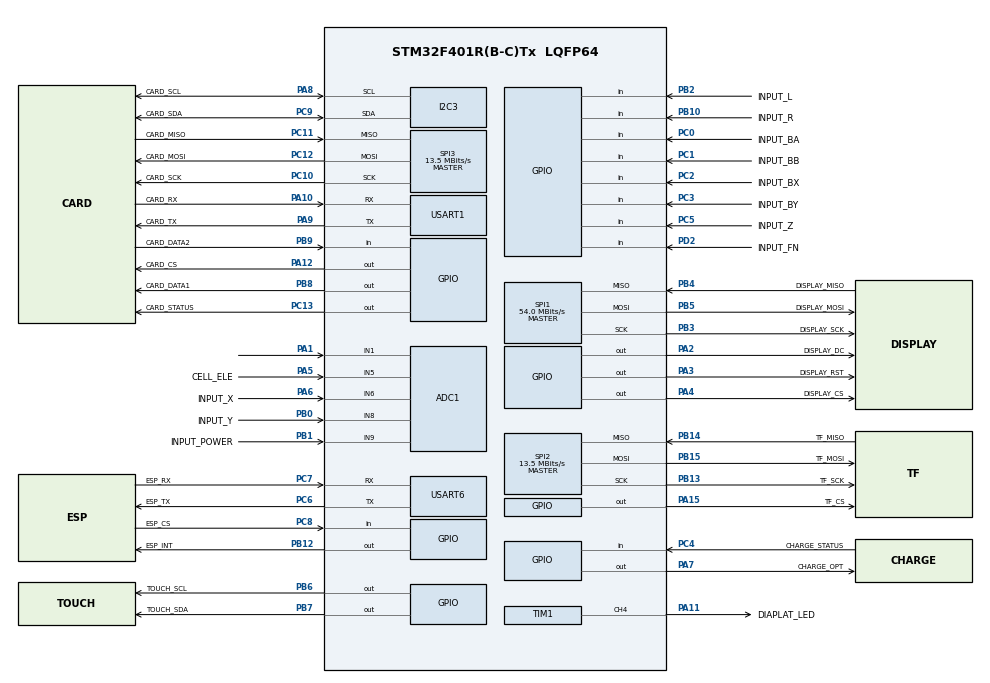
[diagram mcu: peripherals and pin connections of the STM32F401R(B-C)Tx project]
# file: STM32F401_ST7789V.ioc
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ADC1.Channel-1\#ChannelRegularConversion=ADC_CHANNEL_6
ADC1.Channel-10\#ChannelRegularConversion=ADC_CHANNEL_9
ADC1.Channel-11\#ChannelRegularConversion=ADC_CHANNEL_TEMPSENSOR
ADC1.Channel-12\#ChannelRegularConversion=ADC_CHANNEL_VREFINT
ADC1.Channel-7\#ChannelRegularConversion=ADC_CHANNEL_8
ADC1.Channel-8\#ChannelRegularConversion=ADC_CHANNEL_1
ADC1.Channel-9\#ChannelRegularConversion=ADC_CHANNEL_5
ADC1.ContinuousConvMode=ENABLE
ADC1.DMAContinuousRequests=ENABLE
ADC1.DiscontinuousConvMode=DISABLE
ADC1.NbrOfConversion=7
ADC1.NbrOfConversionFlag=1
ADC1.Rank-1\#ChannelRegularConversion=1
ADC1.Rank-10\#ChannelRegularConversion=5
ADC1.Rank-11\#ChannelRegularConversion=6
ADC1.Rank-12\#ChannelRegularConversion=7
ADC1.Rank-7\#ChannelRegularConversion=2
ADC1.Rank-8\#ChannelRegularConversion=3
ADC1.Rank-9\#ChannelRegularConversion=4
ADC1.SamplingTime-1\#ChannelRegularConversion=ADC_SAMPLETIME_3CYCLES
ADC1.SamplingTime-10\#ChannelRegularConversion=ADC_SAMPLETIME_3CYCLES
ADC1.SamplingTime-11\#ChannelRegularConversion=ADC_SAMPLETIME_3CYCLES
ADC1.SamplingTime-12\#ChannelRegularConversion=ADC_SAMPLETIME_3CYCLES
ADC1.SamplingTime-7\#ChannelRegularConversion=ADC_SAMPLETIME_3CYCLES
ADC1.SamplingTime-8\#ChannelRegularConversion=ADC_SAMPLETIME_3CYCLES
ADC1.SamplingTime-9\#ChannelRegularConversion=ADC_SAMPLETIME_3CYCLES
ADC1.ScanConvMode=ENABLE
ADC1.master=1
Dma.ADC1.2.Direction=DMA_PERIPH_TO_MEMORY
Dma.ADC1.2.FIFOMode=DMA_FIFOMODE_DISABLE
Dma.ADC1.2.Instance=DMA2_Stream4
Dma.ADC1.2.MemDataAlignment=DMA_MDATAALIGN_HALFWORD
Dma.ADC1.2.MemInc=DMA_MINC_ENABLE
Dma.ADC1.2.Mode=DMA_CIRCULAR
Dma.ADC1.2.PeriphDataAlignment=DMA_PDATAALIGN_HALFWORD
Dma.ADC1.2.PeriphInc=DMA_PINC_DISABLE
Dma.ADC1.2.Priority=DMA_PRIORITY_LOW
Dma.Request0=SPI1_RX
Dma.Request1=SPI1_TX
Dma.Request2=ADC1
Dma.SPI1_RX.0.Direction=DMA_PERIPH_TO_MEMORY
Dma.SPI1_RX.0.FIFOMode=DMA_FIFOMODE_DISABLE
Dma.SPI1_RX.0.Instance=DMA2_Stream0
Dma.SPI1_RX.0.MemDataAlignment=DMA_MDATAALIGN_BYTE
Dma.SPI1_RX.0.MemInc=DMA_MINC_ENABLE
Dma.SPI1_RX.0.Mode=DMA_NORMAL
Dma.SPI1_RX.0.PeriphDataAlignment=DMA_PDATAALIGN_BYTE
Dma.SPI1_RX.0.PeriphInc=DMA_PINC_DISABLE
Dma.SPI1_RX.0.Priority=DMA_PRIORITY_VERY_HIGH
Dma.SPI1_TX.1.Direction=DMA_MEMORY_TO_PERIPH
Dma.SPI1_TX.1.FIFOMode=DMA_FIFOMODE_DISABLE
Dma.SPI1_TX.1.Instance=DMA2_Stream3
Dma.SPI1_TX.1.MemDataAlignment=DMA_MDATAALIGN_BYTE
Dma.SPI1_TX.1.MemInc=DMA_MINC_ENABLE
Dma.SPI1_TX.1.Mode=DMA_NORMAL
Dma.SPI1_TX.1.PeriphDataAlignment=DMA_PDATAALIGN_BYTE
Dma.SPI1_TX.1.PeriphInc=DMA_PINC_DISABLE
Dma.SPI1_TX.1.Priority=DMA_PRIORITY_VERY_HIGH
Mcu.Family=STM32F4
Mcu.Name=STM32F401R(B-C)Tx
Mcu.Package=LQFP64
NVIC.ADC_IRQn=true\:0\:0\:false\:false\:true\:true\:true\:true
NVIC.DMA2_Stream0_IRQn=true\:0\:0\:false\:false\:true\:false\:true\:true
NVIC.DMA2_Stream3_IRQn=true\:0\:0\:false\:false\:true\:false\:true\:true
NVIC.DMA2_Stream4_IRQn=true\:0\:0\:false\:false\:true\:false\:true\:true
NVIC.PriorityGroup=NVIC_PRIORITYGROUP_4
PA0-WKUP.Mode=SYS_WakeUp0
PA0-WKUP.Signal=SYS_WKUP
PA1.Signal=ADCx_IN1
PA10.GPIO_Label=CARD_RX
PA10.Mode=Asynchronous
PA10.Signal=USART1_RX
PA11.GPIO_Label=DIAPLAT_LED
PA11.Signal=S_TIM1_CH4
PA12.GPIO_Label=CARD_CS
PA12.Signal=GPIO_Output
PA13.Mode=Serial_Wire
PA13.Signal=SYS_JTMS-SWDIO
PA14.Mode=Serial_Wire
PA14.Signal=SYS_JTCK-SWCLK
PA15.GPIO_Label=TF_CS
PA15.Signal=GPIO_Output
PA2.GPIO_Label=DISPLAY_DC
PA2.Signal=GPIO_Output
PA3.GPIO_Label=DISPLAY_RST
PA3.Signal=GPIO_Output
PA4.GPIO_Label=DISPLAY_CS
PA4.Signal=GPIO_Output
PA5.GPIO_Label=CELL_ELE
PA5.Signal=ADCx_IN5
PA6.GPIO_Label=INPUT_X
PA6.Signal=ADCx_IN6
PA7.GPIO_Label=CHARGE_OPT
PA7.Signal=GPIO_Output
PA8.GPIO_Label=CARD_SCL
PA8.Mode=I2C
PA8.Signal=I2C3_SCL
PA9.GPIO_Label=CARD_TX
PA9.Mode=Asynchronous
PA9.Signal=USART1_TX
PB0.GPIO_Label=INPUT_Y
PB0.Signal=ADCx_IN8
PB1.GPIO_Label=INPUT_POWER
PB1.Signal=ADCx_IN9
PB10.GPIO_Label=INPUT_R
PB10.Signal=GPIO_Input
PB12.GPIO_Label=ESP_INT
PB12.Signal=GPIO_Output
PB13.GPIO_Label=TF_SCK
PB13.Mode=Full_Duplex_Master
PB13.Signal=SPI2_SCK
PB14.GPIO_Label=TF_MISO
PB14.Mode=Full_Duplex_Master
PB14.Signal=SPI2_MISO
PB15.GPIO_Label=TF_MOSI
PB15.Mode=Full_Duplex_Master
PB15.Signal=SPI2_MOSI
PB2.GPIO_Label=INPUT_L
PB2.Signal=GPIO_Input
PB3.GPIO_Label=DISPLAY_SCK
PB3.Mode=Full_Duplex_Master
PB3.Signal=SPI1_SCK
PB4.GPIO_Label=DISPLAY_MISO
PB4.Mode=Full_Duplex_Master
PB4.Signal=SPI1_MISO
PB5.GPIO_Label=DISPLAY_MOSI
PB5.Mode=Full_Duplex_Master
PB5.Signal=SPI1_MOSI
PB6.GPIO_Label=TOUCH_SCL
PB6.GPIO_Speed=GPIO_SPEED_FREQ_VERY_HIGH
PB6.Signal=GPIO_Output
PB7.GPIO_Label=TOUCH_SDA
PB7.GPIO_Speed=GPIO_SPEED_FREQ_VERY_HIGH
PB7.Signal=GPIO_Output
PB8.GPIO_Label=CARD_DATA1
PB8.Signal=GPIO_Output
PB9.GPIO_Label=CARD_DATA2
PB9.Signal=GPIO_Input
PC0.GPIO_Label=INPUT_BA
PC0.Signal=GPIO_Input
PC1.GPIO_Label=INPUT_BB
PC1.Signal=GPIO_Input
PC10.GPIO_Label=CARD_SCK
PC10.Mode=Full_Duplex_Master
PC10.Signal=SPI3_SCK
PC11.GPIO_Label=CARD_MISO
PC11.Mode=Full_Duplex_Master
PC11.Signal=SPI3_MISO
PC12.GPIO_Label=CARD_MOSI
PC12.Mode=Full_Duplex_Master
PC12.Signal=SPI3_MOSI
PC13-ANTI_TAMP.GPIO_Label=CARD_STATUS
PC13-ANTI_TAMP.Signal=GPIO_Output
PC14-OSC32_IN.Mode=LSE-External-Oscillator
PC14-OSC32_IN.Signal=RCC_OSC32_IN
PC15-OSC32_OUT.Mode=LSE-External-Oscillator
PC15-OSC32_OUT.Signal=RCC_OSC32_OUT
PC2.GPIO_Label=INPUT_BX
PC2.Signal=GPIO_Input
PC3.GPIO_Label=INPUT_BY
PC3.Signal=GPIO_Input
PC4.GPIO_Label=CHARGE_STATUS
PC4.Signal=GPIO_Input
PC5.GPIO_Label=INPUT_Z
PC5.Signal=GPIO_Input
PC6.GPIO_Label=ESP_TX
PC6.Mode=Asynchronous
PC6.Signal=USART6_TX
PC7.GPIO_Label=ESP_RX
PC7.Mode=Asynchronous
PC7.Signal=USART6_RX
PC8.GPIO_Label=ESP_CS
PC8.Signal=GPIO_Input
PC9.GPIO_Label=CARD_SDA
PC9.Mode=I2C
PC9.Signal=I2C3_SDA
PD2.GPIO_Label=INPUT_FN
PD2.Signal=GPIO_Input
PH0\ -\ OSC_IN.Mode=HSE-External-Oscillator
PH0\ -\ OSC_IN.Signal=RCC_OSC_IN
PH1\ -\ OSC_OUT.Mode=HSE-External-Oscillator
PH1\ -\ OSC_OUT.Signal=RCC_OSC_OUT
ProjectManager.HeapSize=0x200
ProjectManager.StackSize=0x400
ProjectManager.TargetToolchain=STM32CubeIDE
RCC.48MHZClocksFreq_Value=108000000
RCC.AHBFreq_Value=108000000
RCC.APB1CLKDivider=RCC_HCLK_DIV4
RCC.APB1Freq_Value=27000000
RCC.APB1TimFreq_Value=54000000
RCC.APB2Freq_Value=108000000
RCC.APB2TimFreq_Value=108000000
RCC.CortexFreq_Value=108000000
RCC.HCLKFreq_Value=108000000
RCC.HSE_VALUE=25000000
RCC.HSI_VALUE=16000000
RCC.PLLM=25
RCC.PLLN=432
RCC.PLLP=RCC_PLLP_DIV4
RCC.PLLSourceVirtual=RCC_PLLSOURCE_HSE
RCC.SYSCLKFreq_VALUE=108000000
RCC.SYSCLKSource=RCC_SYSCLKSOURCE_PLLCLK
RCC.VCOOutputFreq_Value=432000000
SH.ADCx_IN1.0=ADC1_IN1,IN1
SH.ADCx_IN5.0=ADC1_IN5,IN5
SH.ADCx_IN6.0=ADC1_IN6,IN6
SH.ADCx_IN8.0=ADC1_IN8,IN8
SH.ADCx_IN9.0=ADC1_IN9,IN9
SH.S_TIM1_CH4.0=TIM1_CH4,PWM Generation4 CH4
SPI1.BaudRatePrescaler=SPI_BAUDRATEPRESCALER_2
SPI1.CLKPolarity=SPI_POLARITY_HIGH
SPI1.CalculateBaudRate=54.0 MBits/s
SPI1.DataSize=SPI_DATASIZE_8BIT
SPI1.Direction=SPI_DIRECTION_2LINES
SPI1.Mode=SPI_MODE_MASTER
SPI1.VirtualType=VM_MASTER
SPI2.CalculateBaudRate=13.5 MBits/s
SPI2.Direction=SPI_DIRECTION_2LINES
SPI2.Mode=SPI_MODE_MASTER
SPI2.VirtualType=VM_MASTER
SPI3.CalculateBaudRate=13.5 MBits/s
SPI3.Direction=SPI_DIRECTION_2LINES
SPI3.Mode=SPI_MODE_MASTER
SPI3.VirtualType=VM_MASTER
STMicroelectronics.X-CUBE-ALGOBUILD.1.3.0.LibraryCcDSPOoLibraryJjDSPOoLibrary=true
TIM1.Channel-PWM\ Generation4\ CH4=TIM_CHANNEL_4
TIM1.Period=100-1
TIM1.Prescaler=11
TIM1.Pulse-PWM\ Generation4\ CH4=50
USART1.VirtualMode=VM_ASYNC
USART6.VirtualMode=VM_ASYNC
VP_ADC1_TempSens_Input.Mode=IN-TempSens
VP_ADC1_Vref_Input.Mode=IN-Vrefint
VP_FATFS_VS_Generic.Mode=User_defined
VP_STMicroelectronics.X-CUBE-ALGOBUILD_VS_DSPOoLibraryJjLibrary_1.3.0_1.3.0.Mode=DSPOoLibraryJjLibrary
VP_TIM1_VS_ClockSourceINT.Mode=Internal
board=custom

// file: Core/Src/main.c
/* USER CODE BEGIN Header */
/**
  ******************************************************************************
  * @file           : main.c
  * @brief          : Main program body
  ******************************************************************************
  * @attention
  *
  * Copyright (c) 2024 STMicroelectronics.
  * All rights reserved.
  *
  * This software is licensed under terms that can be found in the LICENSE file
  * in the root directory of this software component.
  * If no LICENSE file comes with this software, it is provided AS-IS.
  *
  ******************************************************************************
  */
/* USER CODE END Header */
#include "main.h"
#include "adc.h"
#include "dma.h"
#include "fatfs.h"
#include "i2c.h"
#include "spi.h"
#include "tim.h"
#include "usart.h"
#include "gpio.h"

/* USER CODE BEGIN Includes */
#include "stdio.h"
#include "ST7789/st7789.h"
#include "FT6336/ft6336.h"
#include "arm_math.h"

#include "ADC/adc.h"
/* USER CODE END Includes */

/* USER CODE BEGIN PTD */

typedef struct {
    uint16_t width;            //LCD 宽度
    uint16_t height;            //LCD 高度
    uint16_t id;                //LCD ID
    uint8_t dir;            //横屏还是竖屏控制：0，竖屏；1，横屏。
    uint16_t wramcmd;        //开始写gram指令
    uint16_t setxcmd;        //设置x坐标指令
    uint16_t setycmd;        //设置y坐标指令
} _lcd_dev;

_lcd_dev lcddev;

/* USER CODE END PTD */

/* USER CODE BEGIN PV */

//FATFS fs;
//FATFS *pfs;
//FIL fil;
//FRESULT fres;
//DWORD fre_clust;
uint32_t totalSpace, freeSpace;
char buffer[100];

uint16_t data[7] = {0};

float da = 0;

uint32_t adc_values[30] = {0};
uint32_t adc1, adc2, adc3, adc4, adc5, adc6, adc7;

/* USER CODE END PV */

void SystemClock_Config(void);

/* USER CODE BEGIN 0 */

float smoothstep(float x) {
  // 将x限制在0到1之间
  // 计算smoothstep值
  return x * x * (3 - 2 * x);
}

/* USER CODE END 0 */

int main(void) {

  /* MCU Configuration--------------------------------------------------------*/

  /* Reset of all peripherals, Initializes the Flash interface and the Systick. */
  HAL_Init();

  /* Configure the system clock */
  SystemClock_Config();

  /* Initialize all configured peripherals */
  MX_GPIO_Init();
  MX_DMA_Init();
  MX_SPI1_Init();
  MX_TIM1_Init();
  MX_USART1_UART_Init();
  MX_FATFS_Init();
  MX_SPI2_Init();
  MX_USART6_UART_Init();
  MX_ADC1_Init();
  MX_I2C3_Init();
  MX_SPI3_Init();
  /* USER CODE BEGIN 2 */
  US_ADC_Init(&hadc1);

  IIC_Init();

  ST7789_Init();
  ST7789_SetLED_PWM(&htim1, TIM_CHANNEL_4, 99);

//  static float rests;
//  rests = arm_sin_f32(PI / 6.0f);

  // HAL_GPIO_WritePin(LED_GPIO_Port, LED_Pin, GPIO_PIN_RESET);

  // ST7789_Fill_Color(WHITE);

  // ST7789_DrawLine(26, 200, 292, 200, BLACK);

  // ST7789_DrawImage(0, 0, 240, 240, knky);
  //  ST7789_Test();

//  if (f_mount(&fs, "", 0) != FR_OK) {
//    // ST7789_WriteString(20, 20, "OK", Font_11x18, RED, BLACK);
//    HAL_GPIO_WritePin(LED_GPIO_Port, LED_Pin, GPIO_PIN_SET);
//  } else {
//    // ST7789_WriteString(20, 20, "ERR", Font_11x18, RED, BLACK);
//    HAL_GPIO_WritePin(LED_GPIO_Port, LED_Pin, GPIO_PIN_RESET);
//  }

  int x, y, temp;
  /* USER CODE END 2 */

  /* Infinite loop */
  /* USER CODE BEGIN WHILE */
  while (1) {

    getXY(&x, &y);
    getTemp(&temp);
    HAL_Delay(100);
    char d[30] = "";
    da = x * 3.3f / 4096.0f;
    sprintf(d, "%.2f", da);

    ST7789_WriteString(200, 200, d, Font_7x10, WHITE, BLACK);

    da = y * 3.3f / 4096.0f;
    sprintf(d, "%.2f", da);
    ST7789_WriteString(200, 220, d, Font_7x10, WHITE, BLACK);

    da = (double) temp * 3.3f / 4096.0f;
//    float temperate = (1.43 - da) / 0.0043 + 25;
//    temperate *= 100;
    sprintf(d, "%f", da);
    ST7789_WriteString(20, 20, d, Font_7x10, BLUE, BLACK);
    /* USER CODE END WHILE */

  }
}

void SystemClock_Config(void) {
  RCC_OscInitTypeDef RCC_OscInitStruct = {0};
  RCC_ClkInitTypeDef RCC_ClkInitStruct = {0};

  /** Configure the main internal regulator output voltage
  */
  __HAL_RCC_PWR_CLK_ENABLE();
  __HAL_PWR_VOLTAGESCALING_CONFIG(PWR_REGULATOR_VOLTAGE_SCALE2);

  /** Initializes the RCC Oscillators according to the specified parameters
  * in the RCC_OscInitTypeDef structure.
  */
  RCC_OscInitStruct.OscillatorType = RCC_OSCILLATORTYPE_HSE;
  RCC_OscInitStruct.HSEState = RCC_HSE_ON;
  RCC_OscInitStruct.PLL.PLLState = RCC_PLL_ON;
  RCC_OscInitStruct.PLL.PLLSource = RCC_PLLSOURCE_HSE;
  RCC_OscInitStruct.PLL.PLLM = 25;
  RCC_OscInitStruct.PLL.PLLN = 500;
  RCC_OscInitStruct.PLL.PLLP = RCC_PLLP_DIV4;
  RCC_OscInitStruct.PLL.PLLQ = 4;
  if (HAL_RCC_OscConfig(&RCC_OscInitStruct) != HAL_OK) {
    // Error_Handler();
  }

  /** Initializes the CPU, AHB and APB buses clocks
  */
  RCC_ClkInitStruct.ClockType = RCC_CLOCKTYPE_HCLK | RCC_CLOCKTYPE_SYSCLK
                                | RCC_CLOCKTYPE_PCLK1 | RCC_CLOCKTYPE_PCLK2;
  RCC_ClkInitStruct.SYSCLKSource = RCC_SYSCLKSOURCE_PLLCLK;
  RCC_ClkInitStruct.AHBCLKDivider = RCC_SYSCLK_DIV1;
  RCC_ClkInitStruct.APB1CLKDivider = RCC_HCLK_DIV4;
  RCC_ClkInitStruct.APB2CLKDivider = RCC_HCLK_DIV1;

  if (HAL_RCC_ClockConfig(&RCC_ClkInitStruct, FLASH_LATENCY_2) != HAL_OK) {
    Error_Handler();
  }
}

void Error_Handler(void) {
  __disable_irq();
  while (1) {
  }
}
